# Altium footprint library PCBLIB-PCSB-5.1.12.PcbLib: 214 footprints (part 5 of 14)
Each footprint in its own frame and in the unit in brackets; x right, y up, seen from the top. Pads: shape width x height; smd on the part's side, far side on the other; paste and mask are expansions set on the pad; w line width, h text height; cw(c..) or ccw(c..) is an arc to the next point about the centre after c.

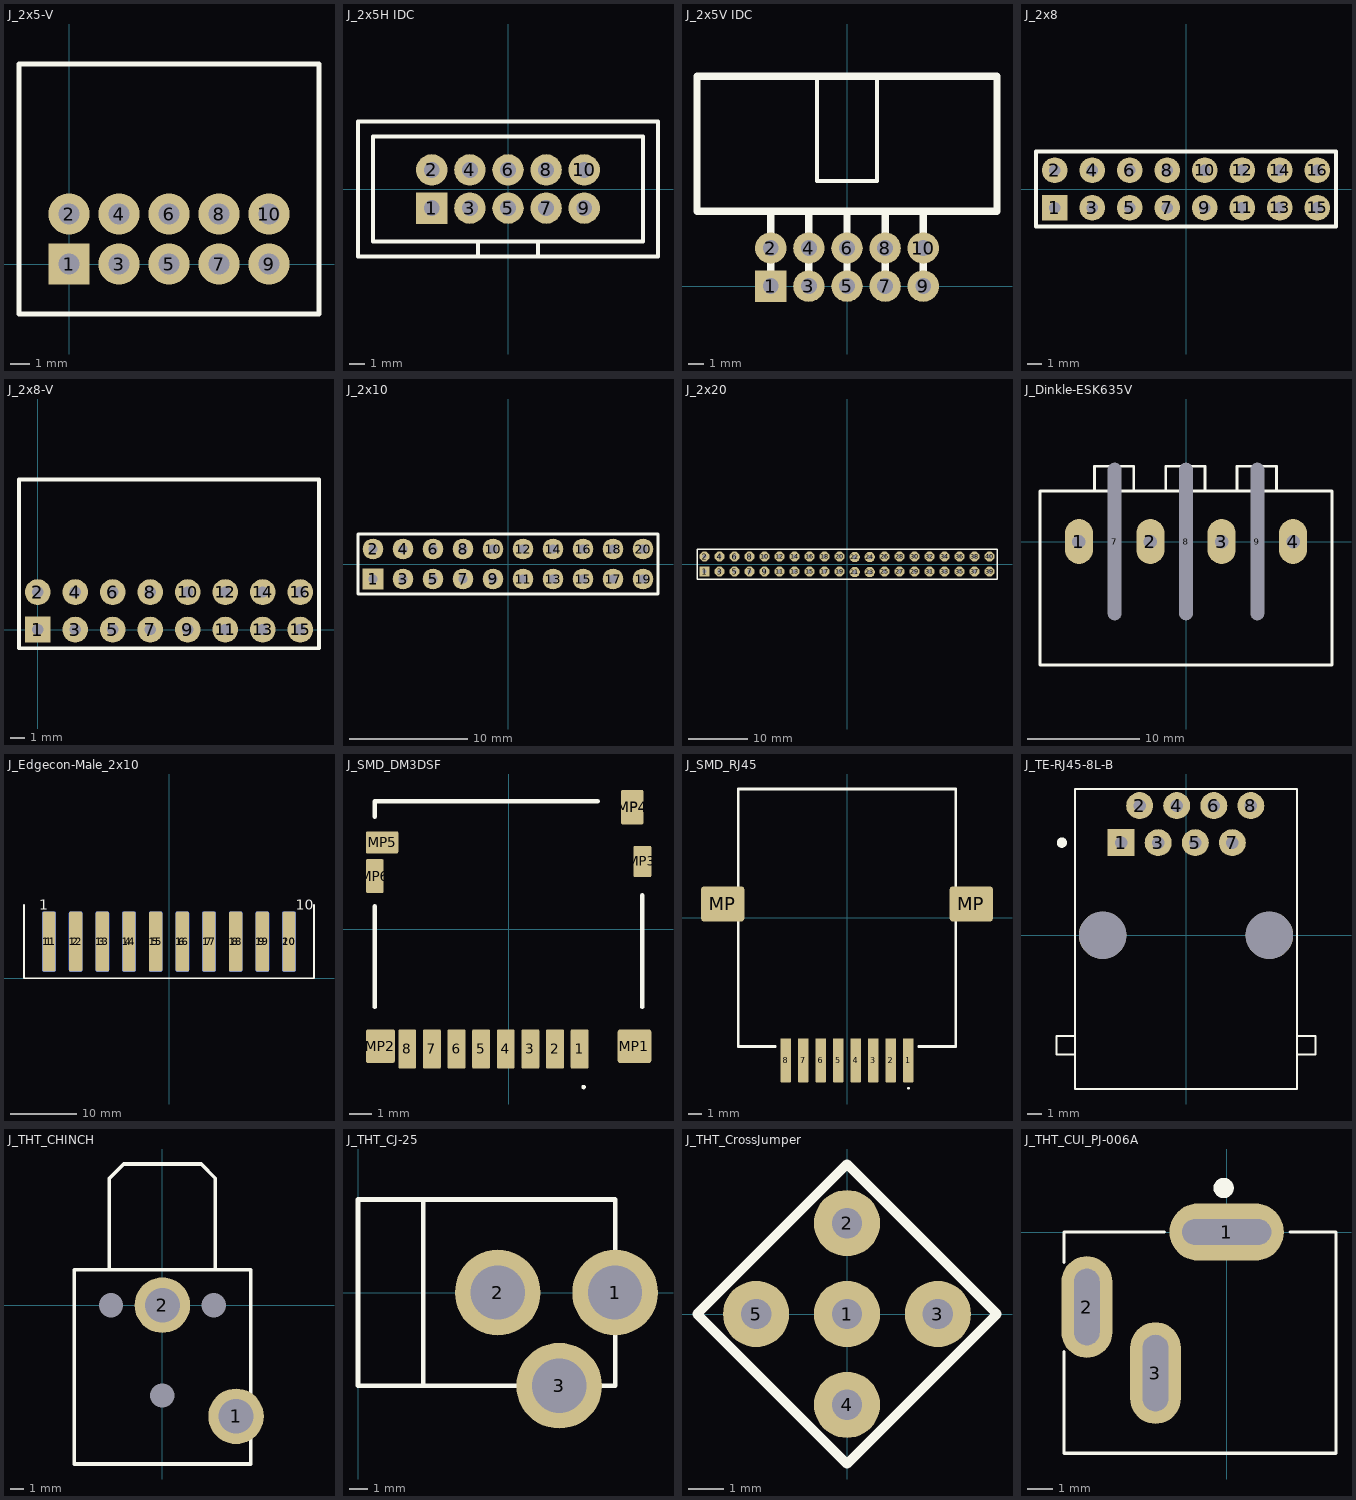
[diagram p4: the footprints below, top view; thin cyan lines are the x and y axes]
## J_2x5-V [mm] "LB-2024-04-19"
height 9
pads (10):
  rect 2.1x2.1 hole 1.05 mask+0.102: 1(0,0)
  round 2.1 hole 1.05 mask+0.102: 2(0,2.54) 3(2.54,0) 4(2.54,2.54) 5(5.08,0) 6(5.08,2.54) 7(7.62,0) 8(7.62,2.54) 9(10.16,0) 10(10.16,2.54)
Top Overlay:
  lines w0.254: -2.54,-2.54 -2.54,10.16 12.7,10.16 12.7,7.62 12.7,-2.54 -2.54,-2.54

## J_2x5H IDC [mm] "LB-2024-04-19"
height 9
pads (10):
  rect 2.1x2.1 hole 1.05 mask+0.102: 1(-5.08,-1.27)
  round 2.1 hole 1.05 mask+0.102: 2(-5.08,1.27) 3(-2.54,-1.27) 4(-2.54,1.27) 5(0,-1.27) 6(0,1.27) 7(2.54,-1.27) 8(2.54,1.27) 9(5.08,-1.27) 10(5.08,1.27)
Top Overlay:
  lines w0.254: -2,-4.5 -2,-3.5 ; -0.5,4.5 10,4.5 10,-4.5 -10,-4.5 -10,4.5 0,4.5 ; 2,-4.5 2,-3.5 ; -9,-3.5 9,-3.5 9,3.5 -9,3.5 -9,-3.5

## J_2x5V IDC [mm] "LB-2024-04-19"
height 9
pads (10):
  rect 2.1x2.1 hole 1.05 mask+0.102: 1(-5.08,0)
  round 2.1 hole 1.05 mask+0.102: 2(-5.08,2.54) 3(-2.54,0) 4(-2.54,2.54) 5(0,0) 6(0,2.54) 7(2.54,0) 8(2.54,2.54) 9(5.08,0) 10(5.08,2.54)
Top Overlay:
  lines w0.254: -2,14 -2,7 2,7 2,14
  lines w0.5: -5.08,0 -5.08,5 ; -2.54,0 -2.54,5 ; 0,0 0,5 ; 2.54,0 2.54,5 ; 5.08,0 5.08,5 ; 0,5 -10,5 -10,14 10,14 10,5 0,5

## J_2x8 [mm] "LB-2024-04-19"
pads (16):
  rect 1.75x1.75 hole 0.75: 1(-8.89,-1.27)
  round 1.75 hole 0.75: 2(-8.89,1.27) 3(-6.35,-1.27) 4(-6.35,1.27) 5(-3.81,-1.27) 6(-3.81,1.27) 7(-1.27,-1.27) 8(-1.27,1.27) 9(1.27,-1.27) 10(1.27,1.27) 11(3.81,-1.27) 12(3.81,1.27) 13(6.35,-1.27) 14(6.35,1.27) 15(8.89,-1.27) 16(8.89,1.27)
Top Overlay:
  lines w0.254: -10.16,-2.54 -10.16,2.54 10.16,2.54 10.16,-2.54 -10.16,-2.54

## J_2x8-V [mm] "LB-2024-04-19"
pads (16):
  rect 1.75x1.75 hole 0.75: 1(0,0)
  round 1.75 hole 0.75: 2(0,2.54) 3(2.54,0) 4(2.54,2.54) 5(5.08,0) 6(5.08,2.54) 7(7.62,0) 8(7.62,2.54) 9(10.16,0) 10(10.16,2.54) 11(12.7,0) 12(12.7,2.54) 13(15.24,0) 14(15.24,2.54) 15(17.78,0) 16(17.78,2.54)
Top Overlay:
  lines w0.254: -1.27,-1.27 -1.27,10.16 19.05,10.16 19.05,-1.27 -1.27,-1.27

## J_2x10 [mm] "LB-2024-4-19"
pads (20):
  rect 1.75x1.75 hole 0.75: 1(-11.43,-1.27)
  round 1.75 hole 0.75: 2(-11.43,1.27) 3(-8.89,-1.27) 4(-8.89,1.27) 5(-6.35,-1.27) 6(-6.35,1.27) 7(-3.81,-1.27) 8(-3.81,1.27) 9(-1.27,-1.27) 10(-1.27,1.27) 11(1.27,-1.27) 12(1.27,1.27) 13(3.81,-1.27) 14(3.81,1.27) 15(6.35,-1.27) 16(6.35,1.27) 17(8.89,-1.27) 18(8.89,1.27) 19(11.43,-1.27) 20(11.43,1.27)
Top Overlay:
  lines w0.254: -12.7,-2.54 12.7,-2.54 12.7,2.54 -12.7,2.54 -12.7,-2.54

## J_2x20 [mm] "LB-2024-4-19"
pads (40):
  rect 1.75x1.75 hole 0.75: 1(-24.13,-1.224)
  round 1.75 hole 0.75: 2(-24.13,1.316) 3(-21.59,-1.224) 4(-21.59,1.316) 5(-19.05,-1.224) 6(-19.05,1.316) 7(-16.51,-1.224) 8(-16.51,1.316) 9(-13.97,-1.224) 10(-13.97,1.316) 11(-11.43,-1.224) 12(-11.43,1.316) 13(-8.89,-1.224) 14(-8.89,1.316) 15(-6.35,-1.224) 16(-6.35,1.316) 17(-3.81,-1.224) 18(-3.81,1.316) 19(-1.27,-1.224) 20(-1.27,1.316) 21(1.296,-1.316) 22(1.296,1.224) 23(3.836,-1.316) 24(3.836,1.224) 25(6.35,-1.224) 26(6.35,1.316) 27(8.89,-1.224) 28(8.89,1.316) 29(11.43,-1.224) 30(11.43,1.316) 31(13.97,-1.224) 32(13.97,1.316) 33(16.51,-1.224) 34(16.51,1.316) 35(19.05,-1.224) 36(19.05,1.316) 37(21.59,-1.224) 38(21.59,1.316) 39(24.13,-1.224) 40(24.13,1.316)
Top Overlay:
  lines w0.254: -25.4,-2.494 25.4,-2.494 25.4,2.586 -25.4,2.586 -25.4,-2.494

## J_Dinkle-ESK635V [mm] "LB-2025-06-18"
pads (7):
  oval 2.5x4 hole 1.2: 1(-9.525,0) 2(-3.175,0) 3(3.175,0) 4(9.525,0)
  oval 1x14 hole 1.2 slot 14 at 90 deg: 7(-6.35,0) 8(0,0) 9(6.35,0)
Top Overlay:
  lines w0.254: -8.15,4.55 -8.15,6.7 -4.65,6.7 -4.65,4.55 ; -1.8,4.5 -1.8,6.7 1.7,6.7 1.7,4.5 ; 0,4.5 13,4.5 ; 4.55,4.55 4.55,6.7 8.05,6.7 8.05,4.55 ; 13,4.5 -13,4.5 -13,-11 13,-11 13,0 13,4.5

## J_Edgecon-Male_2x10 [mm] "PS-2024-06-15"
pads (20):
  rrect25% 2x9 smd paste-0.02 mask+0.05: 1(-18,5.5) 2(-14,5.5) 3(-10,5.5) 4(-6,5.5) 5(-2,5.5) 6(2,5.5) 7(6,5.5) 8(10,5.5) 9(14,5.5) 10(18,5.5)
  rrect25% 2x9 smd far side paste-0.02 mask+0.05: 11(-18,5.5) 12(-14,5.5) 13(-10,5.5) 14(-6,5.5) 15(-2,5.5) 16(2,5.5) 17(6,5.5) 18(10,5.5) 19(14,5.5) 20(18,5.5)
Bottom Layer:
  lines w0.254: -18,8.75 -18,9
Top Overlay:
  lines w0.254: -21.75,11 -21.75,10.75 -21.75,0 0,0 21.75,0 21.75,11
  text "1" at -19.496,10.254 h1.52
  text "10" at 19.004,10.254 h1.52
Bottom Overlay:
  text "11" at -18.754,10.254 h1.52
  text "20" at 21.496,10.254 h1.52

## J_SMD_DM3DSF [mm] "LB-2025-02-19"
pads (14):
  rrect15% 0.8x1.75 smd paste-0.02 mask+0.05: 1(3.175,-5.35) 2(2.075,-5.35) 3(0.975,-5.35) 4(-0.125,-5.35) 5(-1.225,-5.35) 6(-2.325,-5.35) 7(-3.425,-5.35) 8(-4.525,-5.35)
  rrect15% 1.5x1.5 smd paste-0.02 mask+0.05: MP1(5.625,-5.225)
  rrect15% 1.3x1.5 smd paste-0.02 mask+0.05: MP2(-5.725,-5.225)
  rrect15% 0.8x1.4 smd paste-0.02 mask+0.05: MP3(5.975,3.025)
  rrect15% 1x1.55 smd paste-0.02 mask+0.05: MP4(5.525,5.45)
  rrect15% 1.45x1 smd paste-0.02 mask+0.05: MP5(-5.65,3.875)
  rrect15% 0.8x1.5 smd paste-0.02 mask+0.05: MP6(-5.975,2.375)
Top Overlay:
  lines w0.1: 3.35,-7.1 ccw(c3.35,-7.05) 3.35,-7 ccw(c3.35,-7.05) 3.35,-7.1
  lines w0.2: -5.975,-3.475 -5.975,1.025 ; -5.975,5.025 -5.975,5.725 3.975,5.725 ; 5.975,-3.475 5.975,1.525

## J_SMD_RJ45 [mm] "LB-2024-05-31"
pads (10):
  rrect15% 0.76x3.185 smd paste-0.02 mask+0.05: 1(4.445,-10.325) 2(3.175,-10.325) 3(1.905,-10.325) 4(0.635,-10.325) 5(-0.635,-10.325) 6(-1.905,-10.325) 7(-3.175,-10.325) 8(-4.445,-10.325)
  rrect15% 3.12x2.54 smd paste-0.02 mask+0.05: MP(-9,1) MP(9,1)
Top Overlay:
  lines w0.1: 4.445,-12.4 cw(c4.445,-12.35) 4.445,-12.3 cw(c4.445,-12.35) 4.445,-12.4
  lines w0.2: -5.2,-9.325 -7.87,-9.325 -7.87,2.6 -7.87,5.8 -7.87,9.325 7.87,9.325 7.87,2.6 7.87,-9.325 5.2,-9.325

## J_TE-RJ45-8L-B [mm] "LB-2024-11-29"
pads (10):
  rect 1.85x1.85 hole 0.85: 1(-4.445,6.35)
  round 1.85 hole 0.85: 2(-3.175,8.89) 3(-1.905,6.35) 4(-0.635,8.89) 5(0.635,6.35) 6(1.905,8.89) 7(3.175,6.35) 8(4.445,8.89)
  round 3.25 hole 3.25 unplated: ""(-5.715,0) ""(5.715,0)
Top Overlay:
  circle w0.4: c-8.509,6.35 r0.15
  lines w0.127: -7.62,-8.18 -8.89,-8.18 -8.89,-6.91 -7.62,-6.91 ; -7.62,-8.18 -7.62,-6.91 ; -7.62,-8.18 -7.62,-10.54 7.62,-10.54 7.62,-8.18 ; -7.62,-6.91 -7.62,10.03 7.62,10.03 7.62,-6.91 ; 7.62,-8.18 8.89,-8.18 8.89,-6.91 7.62,-6.91 ; 7.62,-8.18 7.62,-6.91

## J_THT_CHINCH [mm] "LB-2024-04-19"
pads (5):
  round 4 hole 2.5: 1(5.3,-8) 2(0,0)
  round 0.5 hole 1.75: 3(-3.7,0) 3(0,-6.5) 3(3.7,0)
Top Overlay:
  lines w0.254: -3.81,2.54 -3.81,9.144 -2.794,10.16 2.794,10.16 3.81,9.144 3.81,2.54 ; -6.35,-11.43 6.35,-11.43 6.35,2.54 5.08,2.54 -5.08,2.54 -6.35,2.54 -6.35,-11.43

## J_THT_CJ-25 [mm] "LB-2024-04-19"
height 1.7
pads (3):
  round 4.6 hole 2.9: 1(13.8,0) 2(7.5,0) 3(10.8,-5)
Top Overlay:
  lines w0.254: 3.5,-5 3.5,5 ; 0,-5 0,5 13.8,5 13.8,-5 0,-5

## J_THT_CrossJumper [mm] "LB-2024-04-19"
pads (5):
  round 1.85 hole 0.85: 1(0,0) 2(0,2.54) 3(2.54,0) 4(0,-2.54) 5(-2.54,0)
Top Overlay:
  lines w0.254: -4.191,0 0,-4.191 4.191,0 0,4.191 -4.191,0

## J_THT_CUI_PJ-006A [mm] "LB-2024-12-12"
pads (3):
  oval 4.5x2.25 hole 1 slot 3.5 at 0 deg: 1(0,0)
  oval 2x4 hole 1 slot 3 at 90 deg: 2(-5.5,-2.95) 3(-2.8,-5.55)
Top Overlay:
  circle w0.4: c-0.12,1.73 r0.2
  lines w0.127: -6.4,-4.7 -6.4,-8.7 4.3,-8.7 4.3,0 2.5,0 ; -6.4,-1.2 -6.4,0 -2.45,0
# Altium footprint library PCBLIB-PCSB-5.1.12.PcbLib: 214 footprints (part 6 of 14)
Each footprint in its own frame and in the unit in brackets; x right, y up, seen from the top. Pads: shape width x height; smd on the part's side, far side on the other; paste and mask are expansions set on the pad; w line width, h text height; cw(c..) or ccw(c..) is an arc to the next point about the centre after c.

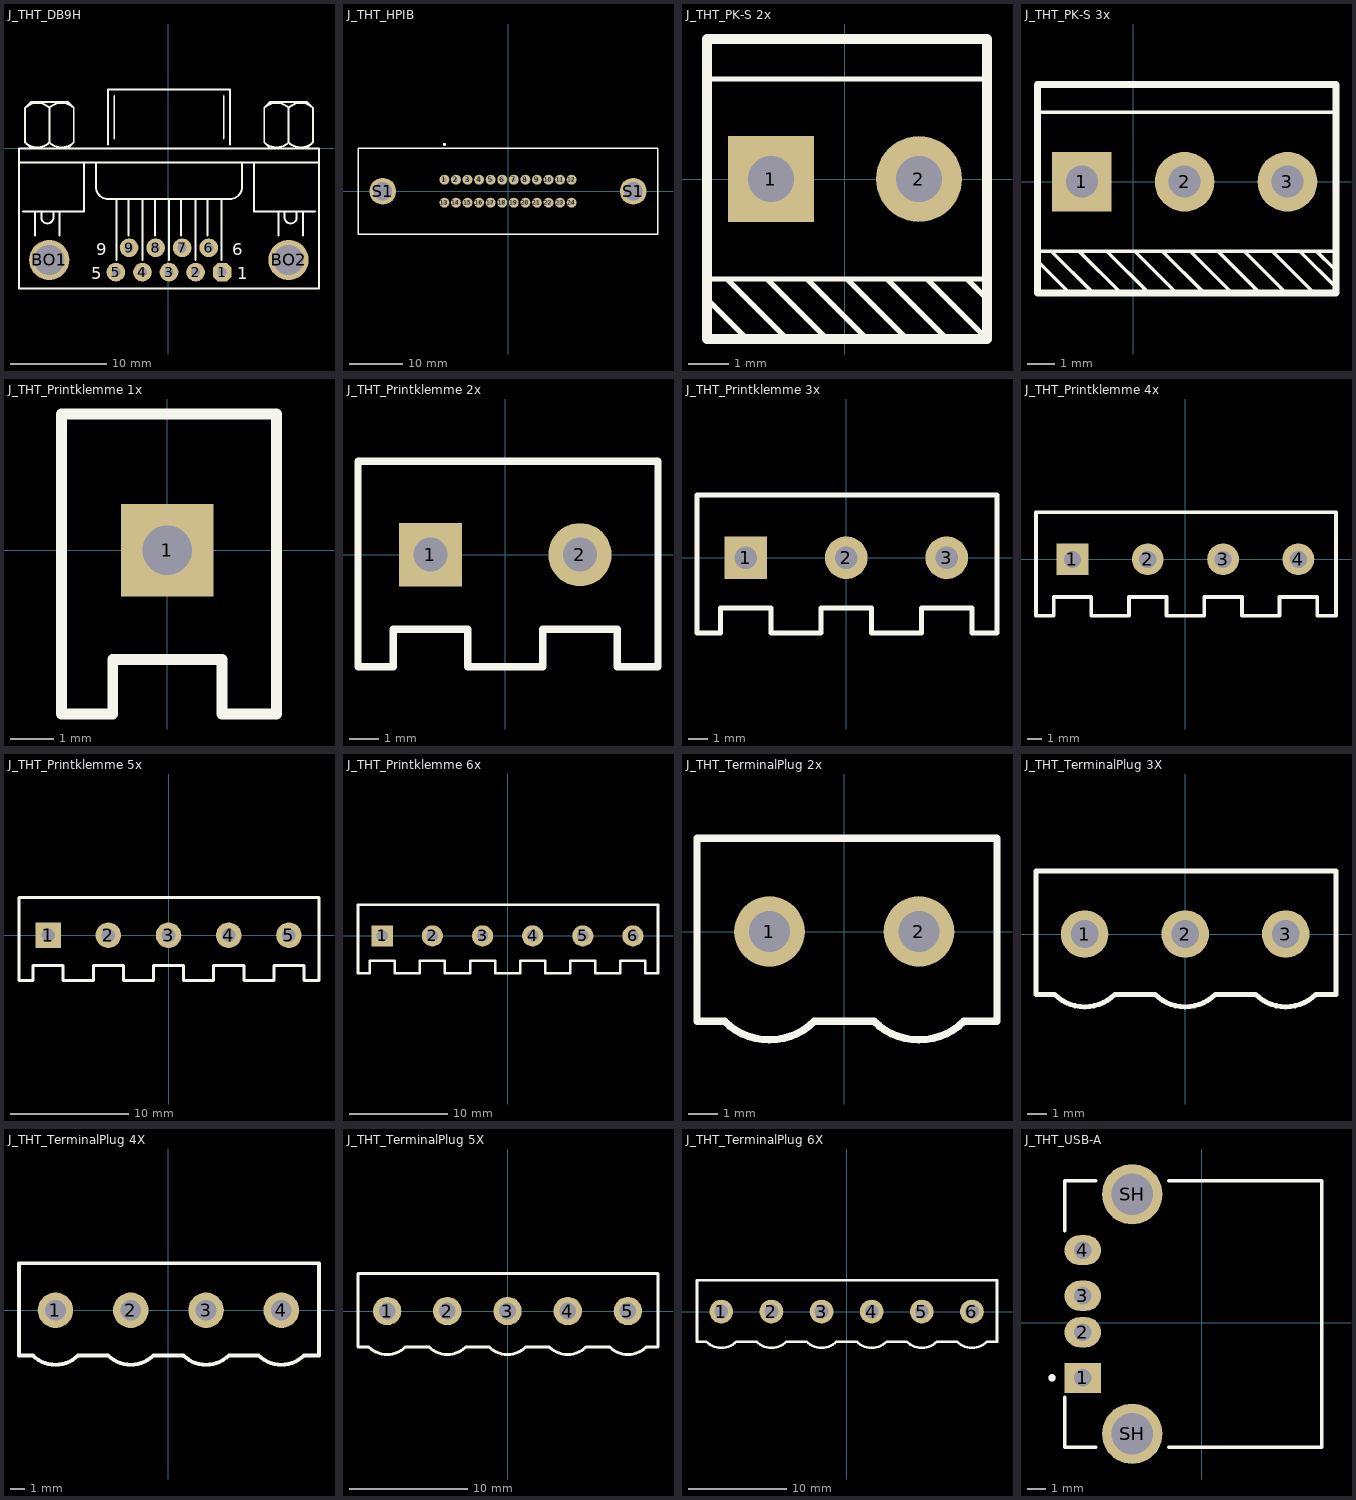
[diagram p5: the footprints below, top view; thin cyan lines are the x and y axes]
## J_THT_DB9H [mm] "LB-2024-04-17"
pads (11):
  oct 1.95x1.95 hole 0.95: 1(5.6,-12.937)
  round 1.95 hole 0.95: 2(2.827,-12.937) 3(0.054,-12.937) 4(-2.718,-12.937) 5(-5.491,-12.937) 6(4.203,-10.397) 7(1.43,-10.397) 8(-1.343,-10.397) 9(-4.115,-10.397)
  round 4.2 hole 3.15: BO1(-12.455,-11.667) BO2(12.543,-11.667)
Top Overlay:
  lines w0.203: -15.609,-1.507 15.718,-1.507 ; -15.186,-6.587 -8.836,-6.587 -8.836,-1.507 ; -14.976,0.608 ccw(c-13.704,1.88) -12.432,0.608 ; -14.976,4.211 cw(c-13.704,2.938) -12.432,4.211 ; -14.339,-0.025 -14.974,0.61 -14.974,4.208 -14.339,4.843 -10.529,4.843 -9.894,4.208 -9.894,0.61 -10.529,-0.025 ; -13.916,-9.127 -13.916,-6.587 ; -13.281,-6.587 -13.281,-7.222 ccw(c-12.646,-7.222) -12.011,-7.222 -12.011,-6.587 ; -12.436,0.608 ccw(c-11.164,1.88) -9.892,0.608 ; -12.436,4.211 cw(c-11.164,2.938) -9.892,4.211 ; -12.434,0.61 -12.434,4.208 ; -11.376,-9.127 -11.376,-6.587 ; -7.566,-1.507 -7.566,-4.047 ccw(c-6.296,-4.047) -6.296,-5.317 6.404,-5.317 ccw(c6.404,-4.047) 7.674,-4.047 7.674,-1.507 ; -6.296,0.398 -6.296,6.113 6.404,6.113 6.404,0.398 ; -5.661,1.033 -5.661,5.478 ; -5.449,-11.667 -5.449,-5.317 ; -4.179,-9.127 -4.179,-5.317 ; -2.697,-11.667 -2.697,-5.317 ; -1.427,-9.127 -1.427,-5.317 ; 0.054,-11.667 0.054,-5.317 ; 1.324,-9.127 1.324,-5.317 ; 2.806,-11.667 2.806,-5.317 ; 4.076,-9.127 4.076,-8.915 4.076,-5.317 ; 5.558,-11.667 5.558,-5.317 ; 5.769,1.033 5.769,5.478 ; 8.944,-1.507 8.944,-6.587 15.294,-6.587 ; 10,0.608 ccw(c11.273,1.88) 12.545,0.608 ; 10,4.211 cw(c11.273,2.938) 12.545,4.211 ; 10.638,-0.025 10.003,0.61 10.003,4.208 10.638,4.843 14.448,4.843 15.083,4.208 15.083,0.61 14.448,-0.025 ; 11.484,-9.127 11.484,-6.587 ; 12.119,-6.587 12.119,-7.222 ccw(c12.754,-7.222) 13.389,-7.222 13.389,-6.587 ; 12.54,0.608 ccw(c13.813,1.88) 15.085,0.608 ; 12.54,4.211 cw(c13.813,2.938) 15.085,4.211 ; 12.543,0.61 12.543,4.208 ; 14.024,-9.127 14.024,-6.587 ; -15.609,-14.63 -15.609,-0.025 15.718,-0.025 15.718,-14.63 -15.609,-14.63
  text "9" at -7.566,-11.159 h1.27
  text "5" at -8.074,-13.699 h1.27
  text "1" at 7.166,-13.699 h1.27
  text "6" at 6.658,-11.159 h1.27

## J_THT_HPIB [mm] "LB-24-10-23"
pads (26):
  round 1.85 hole 0.85: 1(-11.88,2.16) 2(-9.72,2.16) 3(-7.56,2.16) 4(-5.4,2.16) 5(-3.24,2.16) 6(-1.08,2.16) 7(1.08,2.16) 8(3.24,2.16) 9(5.4,2.16) 10(7.56,2.16) 11(9.72,2.16) 12(11.88,2.16) 13(-11.88,-2.13) 14(-9.72,-2.13) 15(-7.56,-2.13) 16(-5.4,-2.13) 17(-3.24,-2.13) 18(-1.08,-2.13) 19(1.08,-2.13) 20(3.24,-2.13) 21(5.4,-2.13) 22(7.56,-2.13) 23(9.72,-2.13) 24(11.88,-2.13)
  round 5 hole 3.5: S1(-23.39,0) S1(23.39,0)
Top Overlay:
  circle w0.4: c-11.88,8.75 r0.1
  lines w0.254: -28.005,-8.005 -28.005,8.005 28.005,8.005 28.005,-8.005 -28.005,-8.005

## J_THT_PK-S 2x [mm] "LB-2024-05-03g"
pads (2):
  rect 2.15x2.15 hole 1.15: 1(-1.85,0)
  round 2.15 hole 1.15: 2(1.85,0)
Top Overlay:
  lines w0.127: -3.45,2.5 3.55,2.5 ; -2.45,-4 -3.45,-3 -3.45,-2.5 3.55,-2.5 ; -1.95,-2.5 -0.45,-4 ; -1.45,-4 -2.95,-2.5 ; -0.95,-2.5 0.55,-4 ; 0.05,-2.5 1.55,-4 ; 1.05,-2.5 2.55,-4 ; 3.55,-4 2.05,-2.5 ; 3.55,-3 3.05,-2.5 ; -2.95,-2.5 -2.95,-2.5 ; 2.05,-2.5 2.05,-2.5 ; 3.05,-2.5 3.05,-2.5 ; 3.05,-2.5 3.05,-2.5
  lines w0.254: -3.45,-4 -3.45,2.365 -3.45,3.5 3.55,3.5 3.55,-4 -2.91,-4 -3.45,-4

## J_THT_PK-S 3x [mm] "LB-2024-05-03g"
pads (3):
  rect 2.15x2.15 hole 1.15: 1(-1.85,0)
  round 2.15 hole 1.15: 2(1.85,0) 3(5.55,0)
Top Overlay:
  lines w0.127: -3.5,-2.5 6.5,-2.5 7.3,-2.5 ; -3.45,2.5 7.3,2.5 ; -3.4,-2.9 -2.3,-4 ; -1.95,-2.5 -0.45,-4 ; -1.45,-4 -2.95,-2.5 ; -0.95,-2.5 0.55,-4 ; 0.05,-2.5 1.55,-4 ; 1.05,-2.5 2.55,-4 ; 3.55,-4 2.05,-2.5 ; 4,-2.5 5.425,-3.925 ; 4.575,-4.025 3.05,-2.5 ; 5,-2.5 6.5,-4 ; 6,-2.5 7.3,-3.8 ; 7,-2.5 6.6,-2.5 7.25,-3.15 ; -2.95,-2.5 -2.95,-2.5 ; 2.05,-2.5 2.05,-2.5 ; 3.05,-2.5 3.05,-2.5 ; 3.05,-2.5 3.05,-2.5
  lines w0.254: -3.45,-4 -3.45,2.365 -3.45,3.5 7.3,3.5 7.3,-4 3.55,-4 -2.91,-4 -3.45,-4

## J_THT_Printklemme 1x [mm] "LB-2024-04-17"
pads (1):
  rect 2.15x2.15 hole 1.15: 1(0,0)
Top Overlay:
  lines w0.254: -2.46,-3.81 -2.46,2.365 -2.46,3.175 2.54,3.175 2.54,-3.81 1.27,-3.81 1.27,-2.54 -1.27,-2.54 -1.27,-3.81 -2.46,-3.81

## J_THT_Printklemme 2x [mm] "LB-2024-04-17"
pads (2):
  rect 2.15x2.15 hole 1.15: 1(-2.54,0)
  round 2.15 hole 1.15: 2(2.54,0)
Top Overlay:
  lines w0.254: 1.27,-3.81 1.27,-2.54 ; 1.27,-3.81 -1.27,-3.81 -1.27,-2.54 -3.81,-2.54 -3.81,-3.81 -5,-3.81 -5,2.365 -5,3.175 5.19,3.175 5.19,-3.81 3.81,-3.81 ; 1.27,-3.81 1.27,-2.54 ; 1.27,-2.54 3.81,-2.54 ; 3.81,-3.81 3.81,-2.54 ; 3.81,-3.81 3.81,-2.54

## J_THT_Printklemme 3x [mm] "LB-2024-04-17"
pads (3):
  rect 2.15x2.15 hole 1.15: 1(-5.08,0)
  round 2.15 hole 1.15: 2(0,0) 3(5.08,0)
Top Overlay:
  lines w0.254: -1.27,-3.81 -1.27,-2.54 ; -1.27,-3.81 -3.81,-3.81 -3.81,-2.54 -6.35,-2.54 -6.35,-3.81 -7.54,-3.81 -7.54,2.365 -7.54,3.175 2.65,3.175 7.62,3.175 7.62,-3.81 6.35,-3.81 6.35,-2.54 3.81,-2.54 3.81,-3.81 1.27,-3.81 ; -1.27,-3.81 -1.27,-2.54 ; -1.27,-2.54 1.27,-2.54 ; 1.27,-3.81 1.27,-2.54 ; 1.27,-3.81 1.27,-2.54

## J_THT_Printklemme 4x [mm] "LB-2024-04-17"
pads (4):
  rect 2.15x2.15 hole 1.15: 1(-7.62,0)
  round 2.15 hole 1.15: 2(-2.54,0) 3(2.54,0) 4(7.62,0)
Top Overlay:
  lines w0.254: -3.81,-3.81 -3.81,-2.54 ; -3.81,-3.81 -6.35,-3.81 -6.35,-2.54 -8.89,-2.54 -8.89,-3.81 -10.08,-3.81 -10.08,2.365 -10.08,3.175 0.11,3.175 10.16,3.175 10.16,-3.81 8.89,-3.81 8.89,-2.54 6.35,-2.54 6.35,-3.81 3.81,-3.81 3.81,-2.54 1.27,-2.54 1.27,-3.81 -1.27,-3.81 ; -3.81,-3.81 -3.81,-2.54 ; -3.81,-2.54 -1.27,-2.54 ; -1.27,-3.81 -1.27,-2.54 ; -1.27,-3.81 -1.27,-2.54

## J_THT_Printklemme 5x [mm] "LB-2024-04-17"
pads (5):
  rect 2.15x2.15 hole 1.15: 1(-10.16,0)
  round 2.15 hole 1.15: 2(-5.08,0) 3(0,0) 4(5.08,0) 5(10.16,0)
Top Overlay:
  lines w0.254: -6.35,-3.81 -6.35,-2.54 ; -6.35,-3.81 -8.89,-3.81 -8.89,-2.54 -11.43,-2.54 -11.43,-3.81 -12.62,-3.81 -12.62,2.365 -12.62,3.175 -2.43,3.175 12.7,3.175 12.7,-3.81 11.43,-3.81 11.43,-2.54 8.89,-2.54 8.89,-3.81 6.35,-3.81 6.35,-2.54 3.81,-2.54 3.81,-3.81 1.27,-3.81 1.27,-2.54 -1.27,-2.54 -1.27,-3.81 -3.81,-3.81 ; -6.35,-3.81 -6.35,-2.54 ; -6.35,-2.54 -3.81,-2.54 ; -3.81,-3.81 -3.81,-2.54 ; -3.81,-3.81 -3.81,-2.54

## J_THT_Printklemme 6x [mm] "LB-2024-04-17"
pads (6):
  rect 2.15x2.15 hole 1.15: 1(-12.7,0)
  round 2.15 hole 1.15: 2(-7.62,0) 3(-2.54,0) 4(2.54,0) 5(7.62,0) 6(12.7,0)
Top Overlay:
  lines w0.254: -8.89,-3.81 -8.89,-2.54 ; -8.89,-3.81 -11.43,-3.81 -11.43,-2.54 -13.97,-2.54 -13.97,-3.81 -15.16,-3.81 -15.16,2.365 -15.16,3.175 -4.97,3.175 15.24,3.175 15.24,-3.81 13.97,-3.81 13.97,-2.54 11.43,-2.54 11.43,-3.81 8.89,-3.81 8.89,-2.54 6.35,-2.54 6.35,-3.81 3.81,-3.81 3.81,-2.54 1.27,-2.54 1.27,-3.81 -1.27,-3.81 -1.27,-2.54 -3.81,-2.54 -3.81,-3.81 -6.35,-3.81 ; -8.89,-3.81 -8.89,-2.54 ; -8.89,-2.54 -6.35,-2.54 ; -6.35,-3.81 -6.35,-2.54 ; -6.35,-3.81 -6.35,-2.54

## J_THT_TerminalPlug 2x [mm] "LB-2024-04-17"
pads (2):
  round 2.4 hole 1.4: 1(-2.54,0) 2(2.54,0)
Top Overlay:
  lines w0.254: -5,-3.048 -4.064,-3.048 ccw(c-2.54,-1.524) -1.016,-3.048 1.016,-3.048 ccw(c2.54,-1.524) 4.064,-3.048 5.19,-3.048 5.19,3.175 -5,3.175 -5,2.365 -5,-3.048

## J_THT_TerminalPlug 3X [mm] "LB-2024-04-17"
pads (3):
  round 2.4 hole 1.4: 1(-5.08,0) 2(0,0) 3(5.08,0)
Top Overlay:
  lines w0.254: -7.54,-3.048 -7.54,2.365 -7.54,3.175 2.65,3.175 7.62,3.175 7.62,-3.048 6.604,-3.048 cw(c5.08,-1.524) 3.556,-3.048 1.524,-3.048 cw(c0,-1.524) -1.524,-3.048 -3.556,-3.048 cw(c-5.08,-1.524) -6.604,-3.048 -7.54,-3.048

## J_THT_TerminalPlug 4X [mm] "LB-2024-04-17"
pads (4):
  round 2.4 hole 1.4: 1(-7.62,0) 2(-2.54,0) 3(2.54,0) 4(7.62,0)
Top Overlay:
  lines w0.254: -10.08,-3.048 -10.08,2.365 -10.08,3.175 0.11,3.175 10.16,3.175 10.16,-3.048 9.144,-3.048 cw(c7.62,-1.524) 6.096,-3.048 4.064,-3.048 cw(c2.54,-1.524) 1.016,-3.048 -1.016,-3.048 cw(c-2.54,-1.524) -4.064,-3.048 -6.096,-3.048 cw(c-7.62,-1.524) -9.144,-3.048 -10.08,-3.048

## J_THT_TerminalPlug 5X [mm] "LB-2024-04-17"
pads (5):
  round 2.4 hole 1.4: 1(-10.16,0) 2(-5.08,0) 3(0,0) 4(5.08,0) 5(10.16,0)
Top Overlay:
  lines w0.254: -12.62,-3.048 -11.684,-3.048 ccw(c-10.16,-1.524) -8.636,-3.048 -6.604,-3.048 ccw(c-5.08,-1.524) -3.556,-3.048 -1.524,-3.048 ccw(c0,-1.524) 1.524,-3.048 3.556,-3.048 ccw(c5.08,-1.524) 6.604,-3.048 8.636,-3.048 ccw(c10.16,-1.524) 11.684,-3.048 12.7,-3.048 12.7,3.175 -2.43,3.175 -12.62,3.175 -12.62,2.365 -12.62,-3.048

## J_THT_TerminalPlug 6X [mm] "LB-2024-04-17"
pads (6):
  round 2.4 hole 1.4: 1(-12.7,0) 2(-7.62,0) 3(-2.54,0) 4(2.54,0) 5(7.62,0) 6(12.7,0)
Top Overlay:
  lines w0.254: -15.16,-3.048 -15.16,2.365 -15.16,3.175 -4.97,3.175 15.24,3.175 15.24,-3.048 14.224,-3.048 cw(c12.7,-1.524) 11.176,-3.048 9.144,-3.048 cw(c7.62,-1.524) 6.096,-3.048 4.064,-3.048 cw(c2.54,-1.524) 1.016,-3.048 -1.016,-3.048 cw(c-2.54,-1.524) -4.064,-3.048 -6.096,-3.048 cw(c-7.62,-1.524) -9.144,-3.048 -11.176,-3.048 cw(c-12.7,-1.524) -14.224,-3.048 -15.16,-3.048

## J_THT_USB-A [mm] "LB-2024-04-29"
pads (6):
  rect 2x1.65 hole 0.95: 1(-6.536,-3.032)
  oval 2x1.65 hole 0.95: 2(-6.536,-0.532) 3(-6.536,1.468) 4(-6.536,3.968)
  round 3.316 hole 2.3: SH(-3.826,-6.102) SH(-3.826,7.038)
Top Overlay:
  circle w0.2: c-8.226,-3.032 r0.1
  lines w0.2: -7.526,-4.097 -7.526,-6.832 -5.836,-6.832 ; -7.526,5.033 -7.526,7.768 -5.836,7.768 ; -1.816,-6.832 6.574,-6.832 6.574,7.768 -1.816,7.768
Mechanical 13:
  circle w0.2: c-8.226,-3.032 r0.1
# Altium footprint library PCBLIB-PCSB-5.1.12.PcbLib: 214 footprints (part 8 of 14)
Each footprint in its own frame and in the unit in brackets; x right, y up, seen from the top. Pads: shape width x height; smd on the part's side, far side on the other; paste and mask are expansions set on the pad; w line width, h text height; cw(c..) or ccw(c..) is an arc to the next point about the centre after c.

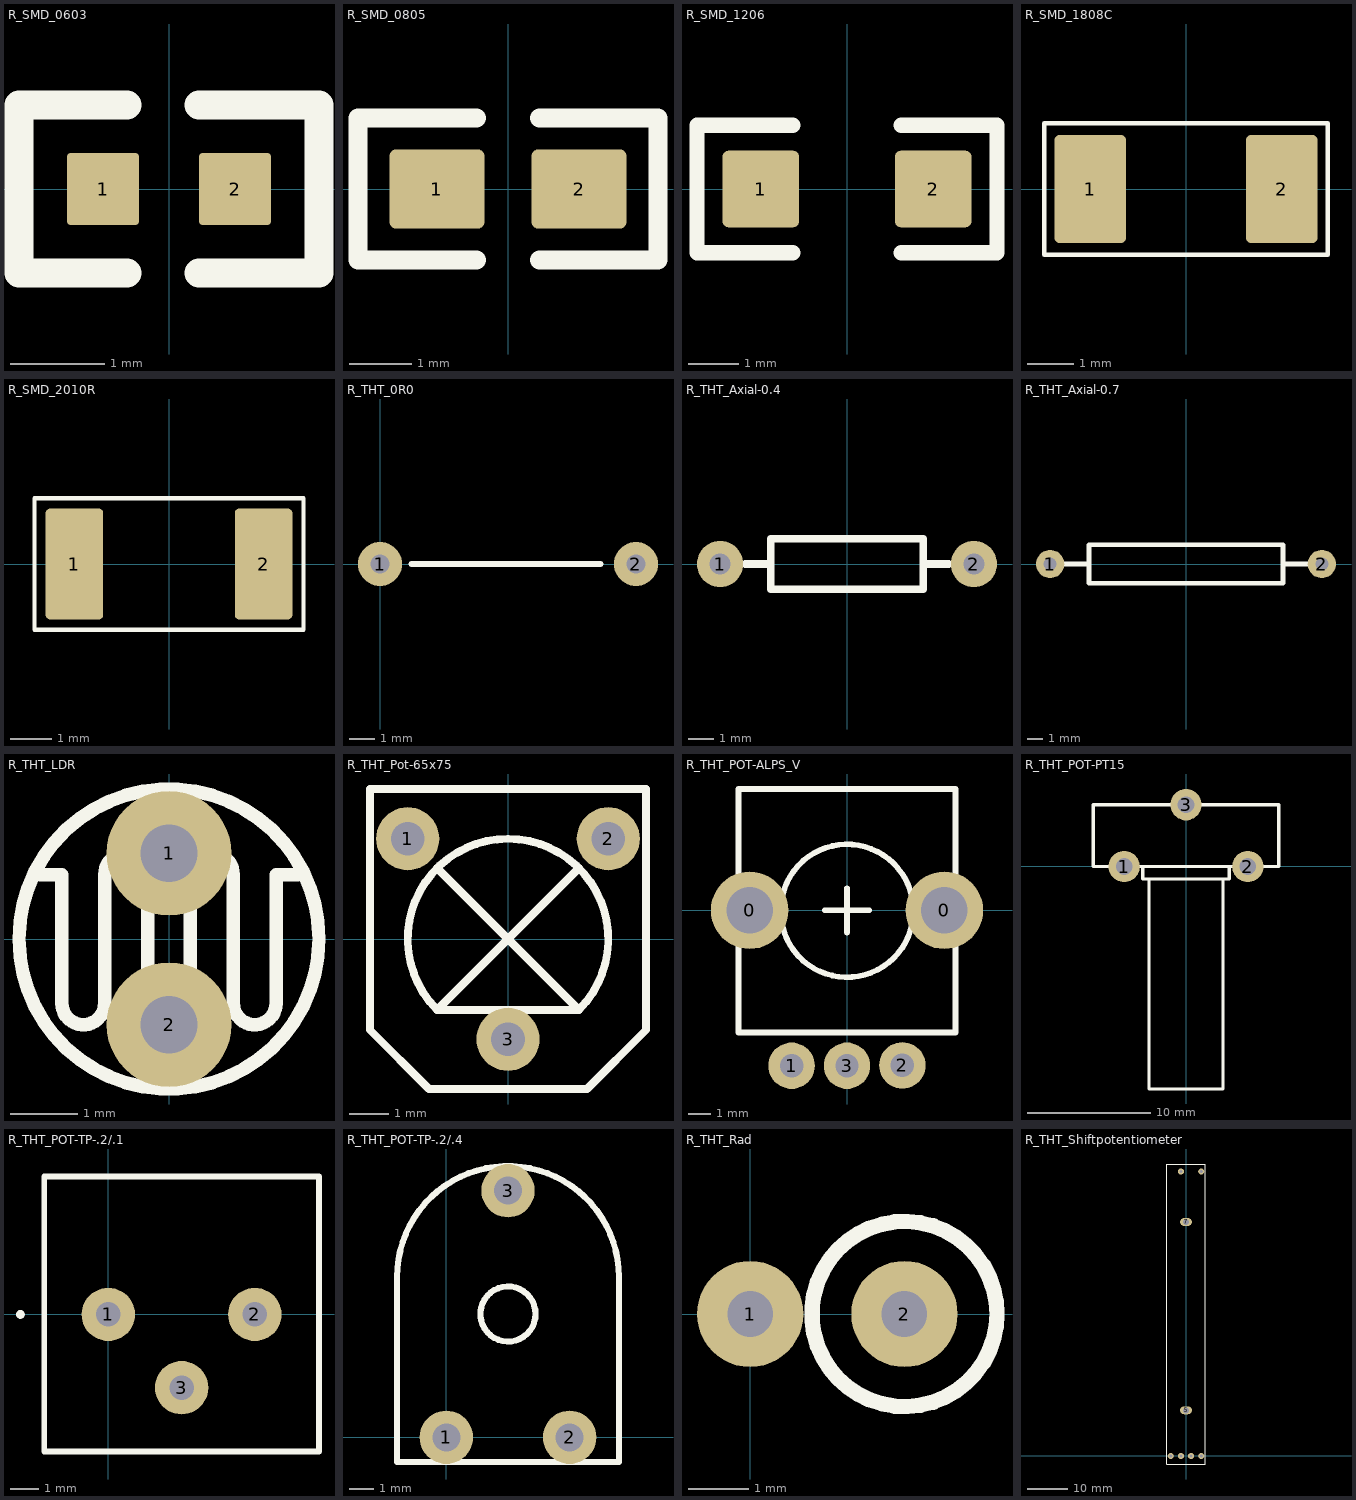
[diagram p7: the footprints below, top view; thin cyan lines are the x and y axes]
## R_SMD_0603 [mil] "LB-2024-04-17"
pads (2):
  rrect10% 30x30 smd paste-0.79 mask+1.97: 1(-27.5,0) 2(27.5,0)
Top Overlay:
  lines w12: -17.5,-35 -62.5,-35 -62.5,35 -17.5,35 ; 12.5,-35 62.5,-35 62.5,35 12.5,35

## R_SMD_0805 [mil] "LB-2024-04-17"
pads (2):
  rrect15% 60x50 smd paste-0.79 mask+1.97: 1(-45,0) 2(45,0)
Top Overlay:
  lines w12: -20,-45 -95,-45 -95,45 -20,45 ; 20,-45 95,-45 95,45 20,45

## R_SMD_1206 [mil] "LB-2024-04-17"
pads (2):
  rrect15% 60x60 smd paste-0.79 mask+1.97: 1(-67.5,0) 2(67.5,0)
Top Overlay:
  lines w12: -42.5,-50 -117.5,-50 -117.5,50 -42.5,50 ; 42.5,-50 117.5,-50 117.5,50 42.5,50

## R_SMD_1808C [mm] "LB-2024-04-17"
height 2
pads (2):
  rrect15% 1.55x2.35 smd paste-0.02 mask+0.05: 1(-2.075,0) 2(2.075,0)
Top Overlay:
  lines w0.1: -3.075,-1.425 -3.075,1.425 3.075,1.425 3.075,-1.425 -3.075,-1.425

## R_SMD_2010R [mm] "LB-2024-04-17"
height 0.7
pads (2):
  rrect15% 1.4x2.7 smd paste-0.02 mask+0.05: 1(-2.3,0) 2(2.3,0)
Top Overlay:
  lines w0.1: -3.275,-1.6 3.275,-1.6 3.275,1.6 -3.275,1.6 -3.275,-1.6

## R_THT_0R0 [mm] "LB-2024-08-13"
pads (2):
  round 1.75 hole 0.75: 1(0,0) 2(10.16,0)
Top Overlay:
  lines w0.254: 1.25,0 8.75,0

## R_THT_Axial-0.4 [mm] "LB-2024-04-17"
pads (2):
  round 1.85 hole 0.85: 1(-5.08,0) 2(5.08,0)
Top Overlay:
  lines w0.305: -4.064,0 -3.048,0 ; 3.048,0 4.064,0 ; -3.048,-1.016 3.048,-1.016 3.048,1.016 -3.048,1.016 -3.048,-1.016

## R_THT_Axial-0.7 [mm] "LB-2024-04-17"
pads (2):
  round 1.85 hole 0.85: 1(-8.89,0) 2(8.89,0)
Top Overlay:
  lines w0.305: -8.89,0 -6.35,0 ; 6.35,0 8.89,0 ; -6.35,-1.27 -6.35,1.27 6.35,1.27 6.35,-1.27 -6.35,-1.27

## R_THT_LDR [mm] "LB-2024-04-18"
pads (2):
  round 1.85 hole 0.85: 1(0,1.27) 2(0,-1.27)
Top Overlay:
  circle w0.2: c0,0 r2.222
  lines w0.2: -1.905,0.953 -1.587,0.953 -1.587,-0.953 ccw(c-1.27,-0.953) -0.953,-0.953 -0.953,0.953 cw(c-0.635,0.953) -0.318,0.953 -0.318,-0.953 ; 0.318,-0.953 0.318,0.953 cw(c0.635,0.953) 0.953,0.953 0.953,-0.953 ccw(c1.27,-0.953) 1.587,-0.953 1.587,0.953 1.905,0.953
Mechanical 13:
  lines w0.2: -0.318,-0.953 ccw(c0,-0.953) 0.318,-0.953

## R_THT_Pot-65x75 [mm]
pads (3):
  round 1.6 hole 0.85: 1(-2.54,2.54) 2(2.54,2.54) 3(0,-2.54)
Top Overlay:
  lines w0.2: -1.796,-1.796 cw(c0,0) 1.796,-1.796 ; 1.792,-1.8 -1.8,-1.8 1.8,1.8 0,0 -1.8,1.8 1.8,-1.8 ; 3.5,-2.2 3.5,-2.3 ; 3.5,-2.3 3.5,0 3.5,3.8 -3.5,3.8 -3.5,-2.3 -2,-3.8 2,-3.8 3.5,-2.3

## R_THT_POT-ALPS_V [mm]
height 15
pads (5):
  round 3.5 hole 2.1: 0(-4.4,0) 0(4.4,0)
  round 2.1 hole 1.05: 1(-2.5,-7.02) 2(2.5,-7) 3(0,-7.02)
Top Overlay:
  circle w0.254: c0,-0.02 r3
  lines w0.254: -1,0 1,0 ; 0,-1 0,0 0,1 ; -4.9,-5.52 -4.9,5.48 4.9,5.48 4.9,-5.52 -4.9,-5.52

## R_THT_POT-PT15 [mm] "LB-2024-04-17"
pads (3):
  round 2.54 hole 1.35: 1(-5.006,-0.011) 2(4.994,-0.011) 3(-0.006,4.989)
Top Overlay:
  lines w0.254: -3.506,-0.011 -3.506,-1.011 3.494,-1.011 3.494,-0.011 ; -3,-1.011 -3,-18 3,-18 3,-1.011 ; -7.506,-0.011 -7.506,4.989 7.494,4.989 7.494,-0.011 -7.506,-0.011

## R_THT_POT-TP-.2/.1 [mm] "LB-2024-12-11"
pads (3):
  round 1.85 hole 0.85: 1(0,0) 2(5.08,0) 3(2.54,-2.54)
Top Overlay:
  lines w0.2: -3.1,0 cw(c-3.05,0) -3,0 ; -3.1,0 ccw(c-3.05,0) -3,0 ; -3.1,0 cw(c-3.05,0) -3,0 ; -2.225,-4.75 -2.225,4.78 7.305,4.78 7.305,-4.75 -2.225,-4.75

## R_THT_POT-TP-.2/.4 [mm] "LB-2024-04-17"
pads (3):
  round 2.2 hole 1.15: 1(0,0) 2(5.08,0) 3(2.54,10.16)
Top Overlay:
  circle w0.254: c2.54,5.08 r1.136
  lines w0.254: -2.032,-1.016 7.112,-1.016 7.112,6.604 ccw(c2.54,6.604) -2.032,6.604 -2.032,-1.016

## R_THT_Rad [mm] "LB-2024-04-17"
pads (2):
  round 1.75 hole 0.75: 1(0,0) 2(2.54,0)
Top Overlay:
  circle w0.254: c2.54,0 r1.524

## R_THT_Shiftpotentiometer [mil] "LB-2025-01-23"
pads (8):
  round 60 hole 30: 1(-150,0) 2(-50,0) 3(50,0) 4(150,0) 5(150,2800) 6(-50,2800)
  oval 118.11x78.74 hole 59.06: 5(0,450) 7(0,2303.15)
Top Overlay:
  lines w10: -187.01,-78.74 0,-78.74 187.01,-78.74 187.01,2874.02 -187.01,2874.02 -187.01,-78.74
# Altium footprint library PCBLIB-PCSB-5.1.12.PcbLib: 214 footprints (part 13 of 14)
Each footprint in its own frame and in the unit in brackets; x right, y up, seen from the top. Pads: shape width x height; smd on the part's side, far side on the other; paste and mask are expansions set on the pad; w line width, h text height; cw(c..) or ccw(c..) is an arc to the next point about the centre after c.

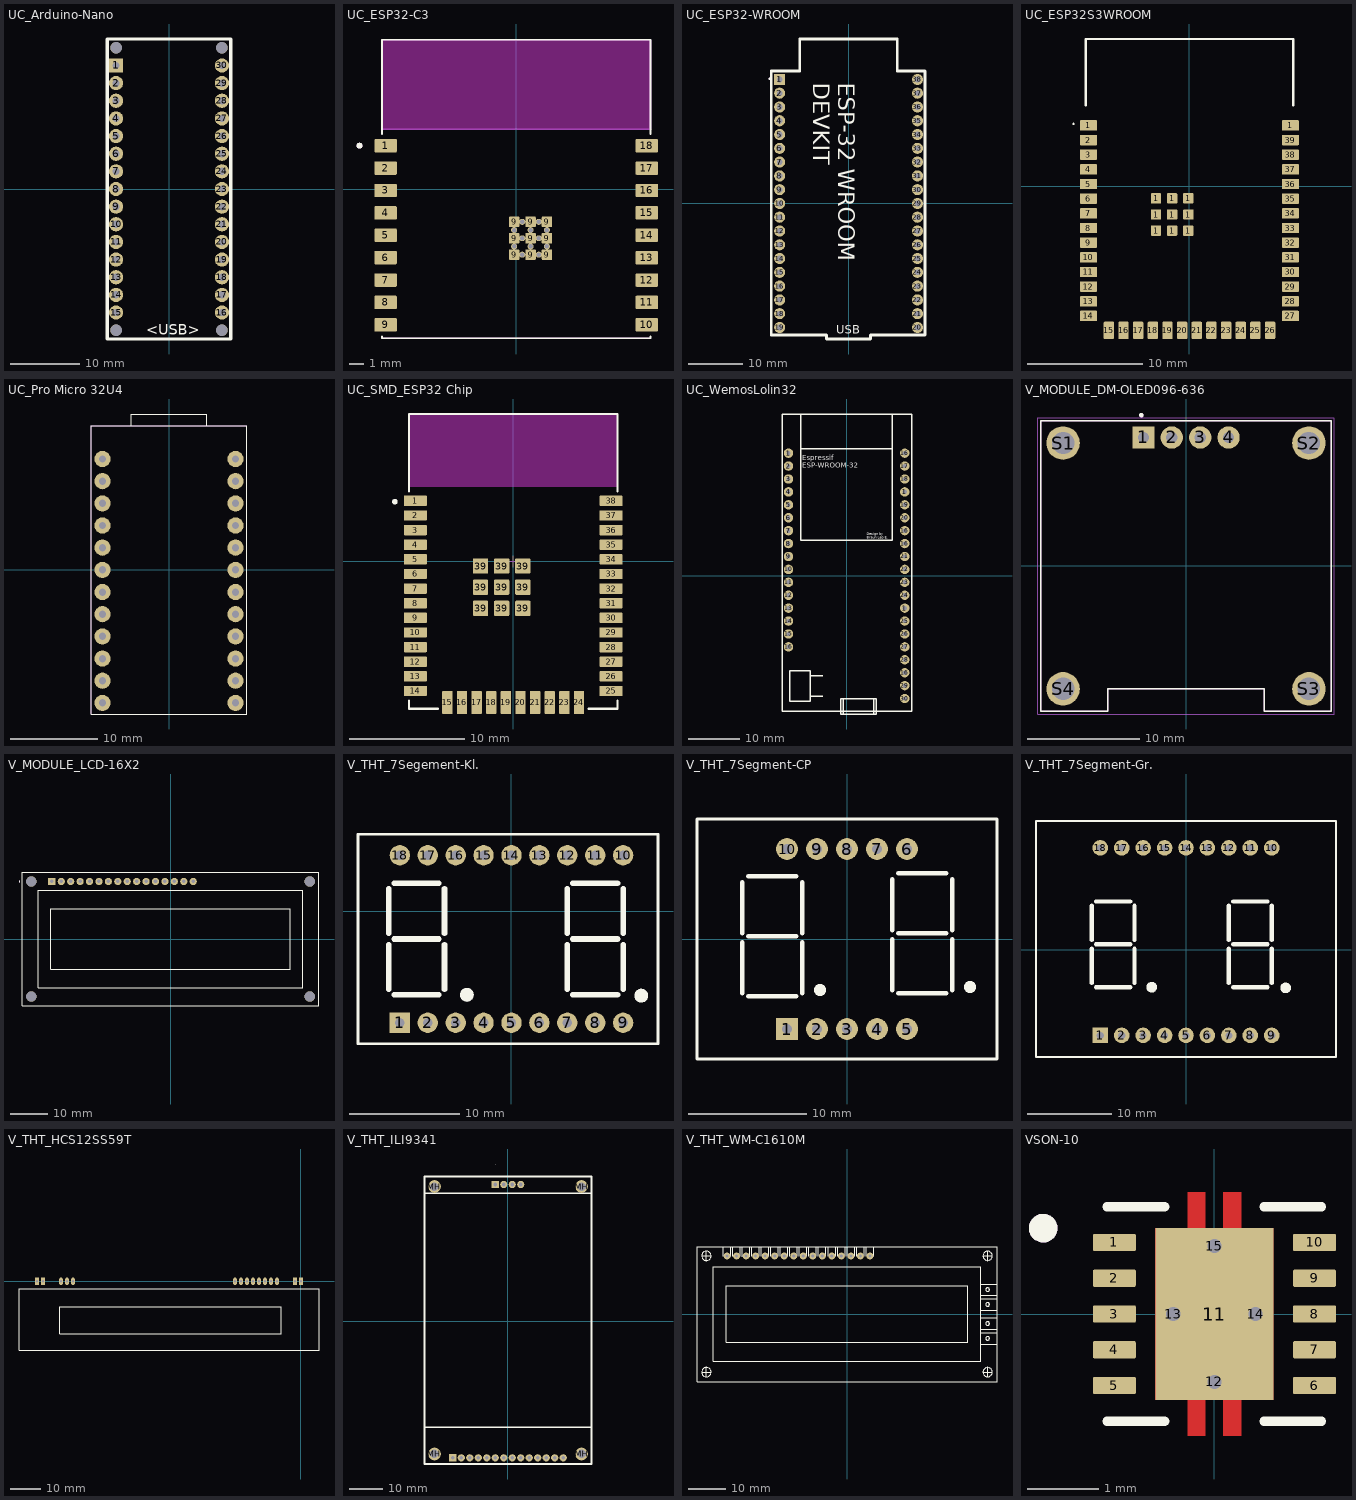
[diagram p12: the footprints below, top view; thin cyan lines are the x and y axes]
## UC_Arduino-Nano [mm] "LB-2024-04-18"
pads (34):
  rect 2.05x2.05 hole 1.05: 1(-7.62,17.78)
  round 2.05 hole 1.05: 2(-7.62,15.24) 3(-7.62,12.7) 4(-7.62,10.16) 5(-7.62,7.62) 6(-7.62,5.08) 7(-7.62,2.54) 8(-7.62,0) 9(-7.62,-2.54) 10(-7.62,-5.08) 11(-7.62,-7.62) 12(-7.62,-10.16) 13(-7.62,-12.7) 14(-7.62,-15.24) 15(-7.62,-17.78) 16(7.62,-17.78) 17(7.62,-15.24) 18(7.62,-12.7) 19(7.62,-10.16) 20(7.62,-7.62) 21(7.62,-5.08) 22(7.62,-2.54) 23(7.62,0) 24(7.62,2.54) 25(7.62,5.08) 26(7.62,7.62) 27(7.62,10.16) 28(7.62,12.7) 29(7.62,15.24) 30(7.62,17.78)
  round 1.651 hole 1.651 unplated: ""(-7.62,-20.32) ""(-7.62,20.32) ""(7.62,-20.32) ""(7.62,20.32)
Top Overlay:
  lines w0.5: -8.89,-21.59 8.89,-21.59 8.89,21.59 -8.89,21.59 -8.89,-21.59
  text "<USB>" at -3.302,-20.955 h1.52

## UC_ESP32-C3 [mm] "LB-2024-09-01"
pads (39):
  rrect15% 1.5x0.9 smd paste-0.02 mask+0.05: 1(-8.75,2.9) 2(-8.75,1.4) 3(-8.75,-0.1) 4(-8.75,-1.6) 5(-8.75,-3.1) 6(-8.75,-4.6) 7(-8.75,-6.1) 8(-8.75,-7.6) 9(-8.75,-9.1) 10(8.75,-9.1) 11(8.75,-7.6) 12(8.75,-6.1) 13(8.75,-4.6) 14(8.75,-3.1) 15(8.75,-1.6) 16(8.75,-0.1) 17(8.75,1.4) 18(8.75,2.9)
  rrect15% 0.7x0.7 smd paste-0.02 mask+0.05: 9(-0.14,-4.4) 9(-0.14,-3.3) 9(-0.14,-2.2) 9(0.96,-4.4) 9(0.96,-3.3) 9(0.96,-2.2) 9(2.06,-4.4) 9(2.06,-3.3) 9(2.06,-2.2)
  round 0.4 hole 0.3 mask+0: 9(-0.14,-3.85) 9(-0.14,-2.75) 9(0.41,-4.4) 9(0.41,-3.3) 9(0.41,-2.2) 9(0.96,-3.85) 9(0.96,-2.75) 9(1.51,-4.4) 9(1.51,-3.3) 9(1.51,-2.2) 9(2.06,-3.85) 9(2.06,-2.75)
Top Overlay:
  circle w0.2: c-10.5,2.9 r0.1
  lines w0.127: -9,-9.87 -9,-10 9,-10 9,-9.87 ; -9,3.67 -9,10 9,10 9,3.67
Keep-Out Layer:
  region: 9,4 -9,4 -9,10 9,10
  region: 9,4 -9,4 -9,10 9,10
Mechanical 13:
  circle w0.2: c-10.5,2.9 r0.1
  lines w0.127: -9,-10 9,-10 ; -9,4 9,4 9,10 -9,10 -9,4

## UC_ESP32-WROOM [mm] "LB-2024-04-18"
pads (38):
  rect 2.05x2.05 hole 1.05: 1(-12.7,22.85)
  round 2.05 hole 1.05: 2(-12.7,20.31) 3(-12.7,17.77) 4(-12.7,15.23) 5(-12.7,12.69) 6(-12.7,10.15) 7(-12.7,7.61) 8(-12.7,5.07) 9(-12.7,2.53) 10(-12.7,-0.01) 11(-12.7,-2.55) 12(-12.7,-5.09) 13(-12.7,-7.63) 14(-12.7,-10.17) 15(-12.7,-12.71) 16(-12.7,-15.25) 17(-12.7,-17.79) 18(-12.7,-20.33) 19(-12.7,-22.87) 20(12.7,-22.87) 21(12.7,-20.33) 22(12.7,-17.79) 23(12.7,-15.25) 24(12.7,-12.71) 25(12.7,-10.17) 26(12.7,-7.63) 27(12.7,-5.09) 28(12.7,-2.55) 29(12.7,-0.01) 30(12.7,2.53) 31(12.7,5.07) 32(12.7,7.61) 33(12.7,10.15) 34(12.7,12.69) 35(12.7,15.23) 36(12.7,17.77) 37(12.7,20.31) 38(12.7,22.85)
Top Overlay:
  circle w0.2: c-14.57,22.97 r0.1
  lines w0.5: -14.224,-24.257 -14.224,24.384 -9,24.384 -9,30.3 9,30.3 9,24.384 14.097,24.384 14.097,-24.257 4.06,-24.257 4.06,-25 -4.07,-25 -4.07,-24.257 -14.224,-24.257
  text "ESP-32 WROOM / DEVKIT" at -6.477,22.225 h3.05
  text "USB" at -2.286,-24.003 h1.52
Mechanical 13:
  circle w0.2: c-14.57,22.97 r0.1

## UC_ESP32S3WROOM [mm] "LB-2025-01-10"
pads (49):
  rrect20% 1.5x0.9 smd paste-0.02 mask+0.05: 1(-8.75,5.26) 1(8.75,5.26) 2(-8.75,3.99) 3(-8.75,2.72) 4(-8.75,1.45) 5(-8.75,0.18) 6(-8.75,-1.09) 7(-8.75,-2.36) 8(-8.75,-3.63) 9(-8.75,-4.9) 10(-8.75,-6.17) 11(-8.75,-7.44) 12(-8.75,-8.71) 13(-8.75,-9.98) 14(-8.75,-11.25) 27(8.75,-11.25) 28(8.75,-9.98) 29(8.75,-8.71) 30(8.75,-7.44) 31(8.75,-6.17) 32(8.75,-4.9) 33(8.75,-3.63) 34(8.75,-2.36) 35(8.75,-1.09) 36(8.75,0.18) 37(8.75,1.45) 38(8.75,2.72) 39(8.75,3.99)
  rrect20% 0.9x0.9 smd paste-0.02 mask+0.05: 1(-2.9,-3.86) 1(-2.9,-2.46) 1(-2.9,-1.06) 1(-1.5,-3.86) 1(-1.5,-2.46) 1(-1.5,-1.06) 1(-0.1,-3.86) 1(-0.1,-2.46) 1(-0.1,-1.06)
  rrect20% 0.9x1.5 smd paste-0.02 mask+0.05: 15(-6.985,-12.5) 16(-5.715,-12.5) 17(-4.445,-12.5) 18(-3.175,-12.5) 19(-1.905,-12.5) 20(-0.635,-12.5) 21(0.635,-12.5) 22(1.905,-12.5) 23(3.175,-12.5) 24(4.445,-12.5) 25(5.715,-12.5) 26(6.985,-12.5)
Top Overlay:
  lines w0.1: -10.1,5.4 ccw(c-10.05,5.4) -10,5.4 ccw(c-10.05,5.4) -10.1,5.4
  lines w0.2: -9,7 -9,12.75 9,12.75 9,7

## UC_Pro Micro 32U4 [mm] "LB-2024-04-18"
pads (24):
  round 1.85 hole 0.85 mask+0.05: J3_1(-7.62,-15.24) J3_2(-7.62,-12.7) J3_3(-7.62,-10.16) J3_4(-7.62,-7.62) J3_5(-7.62,-5.08) J3_6(-7.62,-2.54) J3_7(-7.62,0) J3_8(-7.62,2.54) J3_9(-7.62,5.08) J3_10(-7.62,7.62) J3_11(-7.62,10.16) J3_12(-7.62,12.7) J4_1(7.62,12.7) J4_2(7.62,10.16) J4_3(7.62,7.62) J4_4(7.62,5.08) J4_5(7.62,2.54) J4_6(7.62,0) J4_7(7.62,-2.54) J4_8(7.62,-5.08) J4_9(7.62,-7.62) J4_10(7.62,-10.16) J4_11(7.62,-12.7) J4_12(7.62,-15.24)
Top Overlay:
  lines w0.127: -4.32,16.51 -4.32,17.855 4.32,17.855 4.32,16.51 ; -8.89,-16.51 -8.89,16.51 8.89,16.51 8.89,-16.51 -8.89,-16.51
Mechanical 13:
  lines w0.127: -8.89,-16.51 -8.89,16.51 -4.32,16.51 4.32,16.51 8.89,16.51 8.89,-16.51 -8.89,-16.51

## UC_SMD_ESP32 Chip [mm] "LB-2024-04-18"
pads (47):
  rrect15% 2x0.9 smd paste-0.02 mask+0.05: 1(-8.5,5.26) 2(-8.5,3.99) 3(-8.5,2.72) 4(-8.5,1.45) 5(-8.5,0.18) 6(-8.5,-1.09) 7(-8.5,-2.36) 8(-8.5,-3.63) 9(-8.5,-4.9) 10(-8.5,-6.17) 11(-8.5,-7.44) 12(-8.5,-8.71) 13(-8.5,-9.98) 14(-8.5,-11.25) 25(8.5,-11.25) 26(8.5,-9.98) 27(8.5,-8.71) 28(8.5,-7.44) 29(8.5,-6.17) 30(8.5,-4.9) 31(8.5,-3.63) 32(8.5,-2.36) 33(8.5,-1.09) 34(8.5,0.18) 35(8.5,1.45) 36(8.5,2.72) 37(8.5,3.99) 38(8.5,5.26)
  rrect15% 0.9x2 smd paste-0.02 mask+0.05: 15(-5.715,-12.25) 16(-4.445,-12.25) 17(-3.175,-12.25) 18(-1.905,-12.25) 19(-0.635,-12.25) 20(0.635,-12.25) 21(1.905,-12.25) 22(3.175,-12.25) 23(4.445,-12.25) 24(5.715,-12.25)
  rrect15% 1.33x1.33 smd paste-0.02 mask+0.05: 39(-2.835,-4.075) 39(-2.835,-2.24) 39(-2.835,-0.405) 39(-1,-4.075) 39(-1,-2.24) 39(-1,-0.405) 39(0.835,-4.075) 39(0.835,-2.24) 39(0.835,-0.405)
Top Overlay:
  circle w0.25: c-10.275,5.185 r0.125
  lines w0.2: -9.05,-12.075 -9.05,-12.8 -6.54,-12.8 ; -9.05,6.085 -9.05,12.8 ; 6.54,-12.8 9.05,-12.8 9.05,-12.075 ; 9.05,6.085 9.05,12.8 ; -9.05,12.8 9.05,12.8 ; -9.05,12.8 9.05,12.8
Keep-Out Layer:
  rectangle: -9,6.45 9,12.75
  rectangle: -9,6.45 9,12.75
Mechanical 5:
Mechanical 16:
  lines w0.1: -0.5,0 0.5,0 ; 0,-0.5 0,0.5

## UC_WemosLolin32 [mm] "LB-2024-04-20"
pads (36):
  round 1.85 hole 0.85: 1(-11.43,24.13) 1(11.43,-6.35) 1(11.43,16.51) 2(-11.43,21.59) 3(-11.43,19.05) 4(-11.43,16.51) 5(-11.43,13.97) 6(-11.43,11.43) 7(-11.43,8.89) 8(-11.43,6.35) 9(-11.43,3.81) 10(-11.43,1.27) 11(-11.43,-1.27) 12(-11.43,-3.81) 13(-11.43,-6.35) 14(-11.43,-8.89) 15(-11.43,-11.43) 16(-11.43,-13.97) 16(11.43,-19.05) 16(11.43,6.35) 16(11.43,8.89) 16(11.43,24.13) 17(11.43,21.59) 18(11.43,19.05) 19(11.43,13.97) 20(11.43,11.43) 21(11.43,3.81) 22(11.43,1.27) 23(11.43,-1.27) 24(11.43,-3.81) 25(11.43,-8.89) 26(11.43,-11.43) 27(11.43,-13.97) 28(11.43,-16.51) 29(11.43,-21.59) 30(11.43,-24.13)
Top Overlay:
  lines w0.254: -7.18,-23.67 -4.68,-23.67 ; -7.18,-19.67 -4.68,-19.67 ; -0.68,-24.17 -0.68,-27.17 -1.18,-27.17 ; 0.07,31.83 9,31.83 9,7 -9,7 -9,31.75 -9,25 9,25 ; 5.32,-27.17 5.32,-24.17 ; -1.18,-27.17 -1.18,-26.67 -1.18,-24.17 5.82,-24.17 5.82,-26.67 ; -1.18,-27.17 5.82,-27.17 5.82,-26.67 ; 5.82,-26.67 12.82,-26.67 ; 12.82,-26.67 -12.68,-26.67 -12.68,31.83 12.82,31.83 12.82,-26.67 ; -11.18,-24.67 -11.18,-18.67 -7.18,-18.67 -7.18,-24.67 -11.18,-24.67
  text "Design by / Braun Leo E." at 4,7.25 h0.5
  text "Espressif / ESP-WROOM-32" at -8.75,21.25 h1

## V_MODULE_DM-OLED096-636 [mm]
height 11.3
pads (8):
  rect 2x2 hole 1: 1(-3.81,11.5)
  round 2 hole 1: 2(-1.27,11.5) 3(1.27,11.5) 4(3.81,11.5)
  round 3 hole 2: S1(-11,11) S2(11,11) S3(11,-11) S4(-11,-11)
Top Overlay:
  circle w0.2: c-4,13.5 r0.1
  lines w0.127: -13,-13 -13,13 13,13 13,-13 7,-13 7,-11 -7,-11 -7,-13 -13,-13
Mechanical 13:
  circle w0.2: c-4,13.5 r0.1
  lines w0.127: -13,-13 -13,13 13,13 13,-13 7,-13 7,-11 -7,-11 -7,-13 -13,-13
Mechanical 15:
  lines w0.05: -13.25,-13.25 -13.25,13.25 13.25,13.25 13.25,-13.25 -13.25,-13.25
3D body "step_temp.STEP": height 5.66, standoff -5.64, extent -13,-13 13,13

## V_MODULE_LCD-16X2 [mm] "LB-2024-11-29"
height 14
pads (20):
  rect 1.95x1.95 hole 0.95: 1(-32,15.5)
  round 1.95 hole 0.95: 2(-29.46,15.5) 3(-26.92,15.5) 4(-24.38,15.5) 5(-21.84,15.5) 6(-19.3,15.5) 7(-16.76,15.5) 8(-14.22,15.5) 9(-11.68,15.5) 10(-9.14,15.5) 11(-6.6,15.5) 12(-4.06,15.5) 13(-1.52,15.5) 14(1.02,15.5) 15(3.56,15.5) 16(6.1,15.5)
  round 2.8 hole 2.8 unplated: ""(-37.5,-15.5) ""(-37.5,15.5) ""(37.5,-15.5) ""(37.5,15.5)
Top Overlay:
  circle w0.2: c-40.75,15.5 r0.1
  lines w0.127: -40,-18 -40,18 40,18 40,-18 -40,-18 ; -35.65,-13.15 -35.65,13.15 35.65,13.15 35.65,-13.15 -35.65,-13.15 ; -32.25,-8.2 -32.25,8.2 32.25,8.2 32.25,-8.2 -32.25,-8.2
Mechanical 13:
  circle w0.2: c-40.75,15.5 r0.1

## V_THT_7Segement-Kl. [mm] "LB-2024-04-19"
pads (18):
  rect 1.85x1.85 hole 0.85: 1(-10.16,-10.16)
  round 1.85 hole 0.85: 2(-7.62,-10.16) 3(-5.08,-10.16) 4(-2.54,-10.16) 5(0,-10.16) 6(2.54,-10.16) 7(5.08,-10.16) 8(7.62,-10.16) 9(10.16,-10.16) 10(10.16,5.08) 11(7.62,5.08) 12(5.08,5.08) 13(2.54,5.08) 14(0,5.08) 15(-2.54,5.08) 16(-5.08,5.08) 17(-7.62,5.08) 18(-10.16,5.08)
Top Overlay:
  circle w0.254: c11.811,-7.696 r0.508
  circle w0.254: c-4.064,-7.62 r0.508
  rectangle: 11.405,-8.103 12.217,-7.239
  rectangle: -4.47,-8.026 -3.607,-7.188
  lines w0.254: -13.97,-12.065 13.335,-12.065 13.335,6.985 -13.97,6.985 -13.97,-12.065
  lines w0.508: -11.176,-7.112 -11.176,-3.048 ; -11.176,-2.032 -11.176,2.032 ; -10.668,-7.62 -6.604,-7.62 ; -10.668,-2.54 -6.604,-2.54 ; -10.668,2.54 -6.604,2.54 ; -6.096,-7.112 -6.096,-3.048 ; -6.096,-2.032 -6.096,2.032 ; 5.08,-7.112 5.08,-3.048 ; 5.08,-2.032 5.08,2.032 ; 5.588,-7.62 9.652,-7.62 ; 5.588,-2.54 9.652,-2.54 ; 5.588,2.54 9.652,2.54 ; 10.16,-7.112 10.16,-3.048 ; 10.16,-2.032 10.16,2.032

## V_THT_7Segment-CP [mm] "LB-2024-04-19"
pads (10):
  rect 1.85x1.85 hole 0.85: 1(-5.08,-7.62)
  round 1.85 hole 0.85: 2(-2.54,-7.62) 3(0,-7.62) 4(2.54,-7.62) 5(5.08,-7.62) 6(5.08,7.62) 7(2.54,7.62) 8(0,7.62) 9(-2.54,7.62) 10(-5.08,7.62)
Top Overlay:
  circle w0.508: c10.414,-4.064 r0.254
  circle w0.508: c-2.286,-4.318 r0.254
  lines w0.254: 0,10.16 12.7,10.16 ; 12.7,10.16 12.7,-10.16 -12.7,-10.16 -12.7,10.16 12.7,10.16
  lines w0.381: -8.89,-4.572 -8.89,-0.254 ; -8.89,0.508 -8.89,4.826 ; -8.382,-4.826 -4.318,-4.826 ; -8.382,0.254 -4.318,0.254 ; -8.382,5.334 -4.318,5.334 ; -3.81,-4.572 -3.81,-0.254 ; -3.81,0.508 -3.81,4.826 ; 3.81,-4.318 3.81,0 ; 3.81,0.762 3.81,5.08 ; 4.318,-4.572 8.382,-4.572 ; 4.318,0.508 8.382,0.508 ; 4.318,5.588 8.382,5.588 ; 8.89,-4.318 8.89,0 ; 8.89,0.762 8.89,5.08

## V_THT_7Segment-Gr. [mm] "LB-2024-04-19"
pads (18):
  rect 1.85x1.85 hole 0.85: 1(-10.16,-10.16)
  round 1.85 hole 0.85: 2(-7.62,-10.16) 3(-5.08,-10.16) 4(-2.54,-10.16) 5(0,-10.16) 6(2.54,-10.16) 7(5.08,-10.16) 8(7.62,-10.16) 9(10.16,-10.16) 10(10.16,12.065) 11(7.62,12.065) 12(5.08,12.065) 13(2.54,12.065) 14(0,12.065) 15(-2.54,12.065) 16(-5.08,12.065) 17(-7.62,12.065) 18(-10.16,12.065)
Top Overlay:
  circle w0.254: c11.811,-4.521 r0.508
  circle w0.254: c-4.064,-4.445 r0.508
  rectangle: 11.405,-4.928 12.217,-4.064
  rectangle: -4.47,-4.851 -3.607,-4.013
  lines w0.254: -17.78,-12.7 17.78,-12.7 17.78,15.24 -17.78,15.24 -17.78,-12.7
  lines w0.508: -11.176,-3.937 -11.176,0.127 ; -11.176,1.143 -11.176,5.207 ; -10.668,-4.445 -6.604,-4.445 ; -10.668,0.635 -6.604,0.635 ; -10.668,5.715 -6.604,5.715 ; -6.096,-3.937 -6.096,0.127 ; -6.096,1.143 -6.096,5.207 ; 5.08,-3.937 5.08,0.127 ; 5.08,1.143 5.08,5.207 ; 5.588,-4.445 9.652,-4.445 ; 5.588,0.635 9.652,0.635 ; 5.588,5.715 9.652,5.715 ; 10.16,-3.937 10.16,0.127 ; 10.16,1.143 10.16,5.207

## V_THT_HCS12SS59T [mm] "LB-2026-01-02"
pads (15):
  rect 1.2x2.5 hole 0.75: 1(0,0) 2(-2,0) 44(-86,0) 45(-88,0)
  oval 1.2x2.5 hole 0.75: 5(-8,0) 6(-10,0) 7(-12,0) 8(-14,0) 9(-16,0) 10(-18,0) 11(-20,0) 12(-22,0) 39(-76,0) 40(-78,0) 41(-80,0)
Top Overlay:
  lines w0.4: -94,-23 6,-23 6,-2.5 -94,-2.5 -94,-23 ; -80.5,-17.5 -80.5,-8.5 -6.5,-8.5 -6.5,-17.5 -80.5,-17.5

## V_THT_ILI9341 [mm] "LB-2024-04-19"
pads (22):
  rect 2.15x2.15 hole 1.15: A1(-3.81,40.88) B1(-16.51,-40.88)
  round 2.15 hole 1.15: A2(-1.27,40.88) A3(1.27,40.88) A4(3.81,40.88) B2(-13.97,-40.88) B3(-11.43,-40.88) B4(-8.89,-40.88) B5(-6.35,-40.88) B6(-3.81,-40.88) B7(-1.27,-40.88) B8(1.27,-40.88) B9(3.81,-40.88) B10(6.35,-40.88) B11(8.89,-40.88) B12(11.43,-40.88) B13(13.97,-40.88) B14(16.51,-40.88)
  round 3.81 hole 2.54: MH(-22,-39.73) MH(-22,40.27) MH(22,-39.73) MH(22,40.27)
Top Overlay:
  lines w0.1: -3.81,46.92 cw(c-3.81,46.97) -3.81,47.02 cw(c-3.81,46.97) -3.81,46.92
  lines w0.5: -25,-31.73 25,-31.73 ; -25,38.27 25,38.27 ; -25,-42.73 -25,43.27 25,43.27 25,1.27 25,-42.73 -25,-42.73

## V_THT_WM-C1610M [mm] "LB-2024-04-19"
pads (16):
  round 1.85 hole 0.85: 1(-32,15.5) 2(-29.46,15.5) 3(-26.92,15.5) 4(-24.38,15.5) 5(-21.84,15.5) 6(-19.3,15.5) 7(-16.76,15.5) 8(-14.22,15.5) 9(-11.68,15.5) 10(-9.14,15.5) 11(-6.6,15.5) 12(-4.06,15.5) 13(-1.52,15.5) 14(1.02,15.5) 15(3.56,15.5) 16(6.1,15.5)
Top Overlay:
  circle w0.2: c-37.51,15.538 r1.25
  circle w0.2: c-37.51,-15.462 r1.25
  circle w0.2: c37.49,15.538 r1.25
  circle w0.2: c37.49,6.538 r0.5
  circle w0.2: c37.49,2.578 r0.5
  circle w0.2: c37.49,-2.502 r0.5
  circle w0.2: c37.49,-6.462 r0.5
  circle w0.2: c37.49,-15.462 r1.25
  lines w0.1: -38.75,-15.462 -36.26,-15.462 ; -38.75,15.538 -36.26,15.538 ; -37.51,-16.75 -37.51,-14.25 ; -37.51,14.25 -37.51,16.75 ; 36.25,-15.462 38.74,-15.462 ; 36.25,15.538 38.74,15.538 ; 37.49,-16.75 37.49,-14.25 ; 37.49,14.25 37.49,16.75
  lines w0.2: -33.01,15.498 -33.01,18.038 ; -31.01,15.498 -31.01,18.038 ; -30.47,15.498 -30.47,18.038 ; -28.47,15.498 -28.47,18.038 ; -27.93,15.338 -27.93,18.038 ; -25.93,15.338 -25.93,18.038 ; -25.39,15.498 -25.39,18.038 ; -23.39,15.498 -23.39,18.038 ; -22.85,15.498 -22.85,18.038 ; -20.85,15.498 -20.85,18.038 ; -20.31,15.498 -20.31,18.038 ; -18.31,15.498 -18.31,18.038 ; -17.77,15.498 -17.77,18.038 ; -15.77,15.498 -15.77,18.038 ; -15.23,15.498 -15.23,18.038 ; -13.23,15.498 -13.23,18.038 ; -12.69,15.498 -12.69,18.038 ; -10.69,15.498 -10.69,18.038 ; -10.15,15.468 -10.15,18.038 ; -8.15,15.468 -8.15,18.038 ; -7.61,15.468 -7.61,18.038 ; -5.61,15.468 -5.61,18.038 ; -5.07,15.498 -5.07,18.038 ; -3.07,15.498 -3.07,18.038 ; -2.53,15.498 -2.53,18.038 ; -0.53,15.498 -0.53,18.038 ; 0.01,15.498 0.01,18.038 ; 2.01,15.498 2.01,18.038 ; 2.55,15.498 2.55,18.038 ; 4.55,15.498 4.55,18.038 ; 5.09,15.498 5.09,18.038 ; 7.09,15.498 7.09,18.038 ; 35.59,-7.962 39.99,-7.962 ; 35.59,-4.962 39.99,-4.962 ; 35.59,-4.002 39.99,-4.002 ; 35.59,-1.002 39.99,-1.002 ; 35.59,1.078 39.99,1.078 ; 35.59,4.078 39.99,4.078 ; 35.59,5.038 39.99,5.038 ; 35.59,8.038 39.99,8.038 ; -40.01,-17.962 39.99,-17.962 39.99,18.038 -40.01,18.038 -40.01,-17.962 ; -35.61,-12.562 -35.61,12.638 35.59,12.638 35.59,-12.562 -35.61,-12.562 ; -32.24,-7.462 32.22,-7.462 32.22,7.538 -32.24,7.538 -32.24,-7.462

## VSON-10 [mm] "LB-2024-09-01"
pads (15):
  rrect15% 0.6x0.24 smd paste-0.02 mask+0.05: 1(-1.4,1) 2(-1.4,0.5) 3(-1.4,0) 4(-1.4,-0.5) 5(-1.4,-1) 6(1.4,-1) 7(1.4,-0.5) 8(1.4,0) 9(1.4,0.5) 10(1.4,1)
  rect 1.65x2.4 smd paste-0.02 mask+0.05: 11(0,0)
  round 0.3 hole 0.2 mask+0: 12(0,-0.95) 13(-0.575,0) 14(0.575,0) 15(0,0.95)
Top Layer:
  region: 0.375,1.2 0.825,1.2 0.825,-1.2 0.375,-1.2 0.375,-1.7 0.125,-1.7 0.125,-1.2 -0.125,-1.2 -0.125,-1.7 -0.375,-1.7 -0.375,-1.2 -0.825,-1.2 -0.825,1.2 -0.375,1.2 -0.375,1.7 -0.125,1.7 -0.125,1.2 0.125,1.2 0.125,1.7 0.375,1.7
Top Overlay:
  circle w0.2: c-2.395,1.2 r0.1
  lines w0.127: -1.5,-1.5 -0.695,-1.5 ; -1.5,1.5 -0.695,1.5 ; 0.695,-1.5 1.5,-1.5 ; 0.695,1.5 1.5,1.5
Top Paste:
  region: -0.125,1.36 -0.375,1.36 -0.375,1.7 -0.125,1.7
  region: 0.375,1.36 0.125,1.36 0.125,1.7 0.375,1.7
  region: 0.375,-1.7 0.125,-1.7 0.125,-1.36 0.375,-1.36
  region: -0.125,-1.7 -0.375,-1.7 -0.375,-1.36 -0.125,-1.36
  region: 0.75,0.1 -0.75,0.1 -0.75,1.16 0.75,1.16
  region: 0.75,-1.16 -0.75,-1.16 -0.75,-0.1 0.75,-0.1
Mechanical 13:
  circle w0.2: c-2.395,1.2 r0.1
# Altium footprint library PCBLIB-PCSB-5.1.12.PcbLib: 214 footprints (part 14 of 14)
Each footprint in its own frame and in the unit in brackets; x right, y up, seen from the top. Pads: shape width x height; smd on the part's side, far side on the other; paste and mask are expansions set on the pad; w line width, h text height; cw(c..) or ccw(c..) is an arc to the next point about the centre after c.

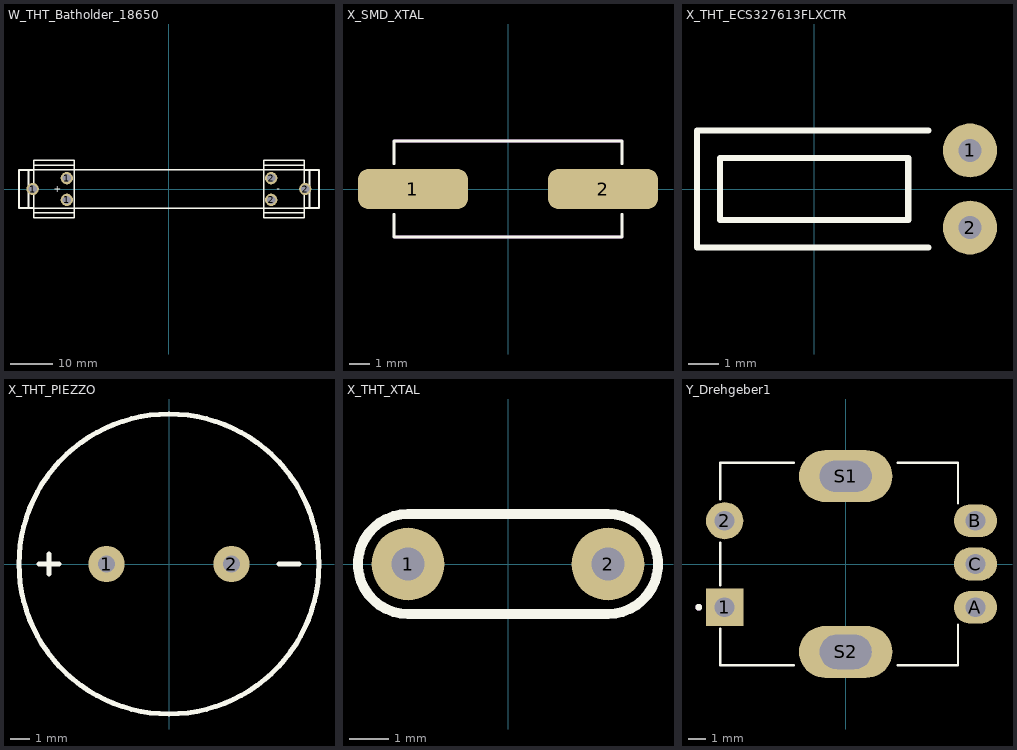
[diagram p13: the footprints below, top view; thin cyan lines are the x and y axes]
## W_THT_Batholder_18650 [mm] "LB-2024-04-25"
height 17
pads (6):
  round 2.9 hole 1.9: 1(-32,0) 1(-24,-2.54) 1(-24,2.54) 2(24.006,-2.54) 2(24.006,2.54) 2(32,0)
Top Overlay:
  lines w0.4: -31.74,-6.75 -22.27,-6.75 ; -31.74,-6.71 -31.74,-5.552 -29.08,-5.552 -22.272,-5.552 ; -31.74,-5.492 -31.74,5.552 ; -31.74,-4.45 -35.22,-4.45 -35.22,4.45 -31.74,4.45 ; -31.74,6.71 -31.74,5.552 ; -31.74,6.75 -22.27,6.75 ; -22.272,5.552 -29.08,5.552 -31.74,5.552 ; -22.22,-6.75 -22.22,-5.552 -22.22,5.552 -22.22,6.75 ; 22.226,-6.75 22.226,-5.552 22.226,5.552 22.226,6.75 ; 22.276,-6.75 31.746,-6.75 ; 22.276,6.75 31.746,6.75 ; 22.278,-5.552 29.086,-5.552 31.746,-5.552 ; 22.278,5.552 29.086,5.552 31.746,5.552 31.746,6.71 ; 31.746,-6.71 31.746,-5.552 ; 31.746,-4.45 35.226,-4.45 35.226,4.45 31.746,4.45 ; 31.746,5.492 31.746,-5.552 ; -33,-4.5 33,-4.5 33,0 33,4.5 -33,4.5 -33,0 -33,-4.5
  text "+" at -25.3,0.7 h1.52
  text "-" at 25.3,-0.7 h1.52

## X_SMD_XTAL [mm] "LB-2024-04-17"
pads (2):
  rrect50% 5.5x2 smd paste-0.02 mask+0.05: 1(-4.75,0) 2(4.75,0)
Top Overlay:
  lines w0.127: -5.7,-1.254 -5.7,-2.4 5.7,-2.4 5.7,-1.254 ; -5.7,1.254 -5.7,2.4 5.7,2.4 5.7,1.254
Mechanical 13:
  lines w0.127: -5.7,-2.4 5.7,-2.4 ; -5.7,2.4 5.7,2.4

## X_THT_ECS327613FLXCTR [mm] "LB-2025-06-22"
pads (2):
  round 1.75 hole 0.75: 1(5.05,1.25) 2(5.05,-1.25)
Top Overlay:
  lines w0.2: 3.7,-1.9 -3.8,-1.9 -3.8,1.9 3.7,1.9 ; 3.05,-1 3.05,1 ; 3.05,-1 3.05,1 ; 3.05,-1 2.8,-1 3.05,-1 ; 3.05,-1 -3.05,-1 -3.05,1 3.05,1 ; 3.05,1 2.8,1 3.05,1
Mechanical 13:
  lines w0.1: 3.05,-1 3.05,1

## X_THT_PIEZZO [mm] "LB-2024-04-18"
pads (2):
  round 1.85 hole 0.85: 1(-3.175,0) 2(3.175,0)
Top Overlay:
  circle w0.254: c0,0 r7.62
  lines w0.254: -6.604,0 -5.588,0 ; -6.096,-0.508 -6.096,0.508 ; 5.588,0 6.604,0

## X_THT_XTAL [mm] "LB-2024-04-17"
pads (2):
  round 1.85 hole 0.85: 1(-2.54,0) 2(2.54,0)
Top Overlay:
  lines w0.254: -2.54,-1.27 cw(c-2.54,0) -2.54,1.27 2.54,1.27 cw(c2.54,0) 2.54,-1.27 -2.54,-1.27

## Y_Drehgeber1 [mm] "LB-2024-04-19"
pads (7):
  rect 2.15x2.15 hole 1.15: 1(-7,-2.5)
  round 2.15 hole 1.15: 2(-7,2.5)
  oval 2.5x1.9 hole 1.15: A(7.5,-2.5) B(7.5,2.5) C(7.5,0)
  oval 5.4x3 hole 1.8 slot 3 at 0 deg: S1(0,5.08)
  oval 5.4x3 hole 2 slot 3 at 0 deg: S2(0,-5.08)
Top Overlay:
  circle w0.2: c-8.5,-2.5 r0.1
  lines w0.127: -7.25,-3.75 -7.25,-5.85 -3,-5.85 ; -7.25,-1.25 -7.25,1.25 ; -7.25,3.75 -7.25,5.85 -3,5.85 ; 3,-5.85 6.5,-5.85 6.5,-3.5 ; 3,5.85 6.5,5.85 6.5,3.5
Mechanical 13:
  circle w0.2: c-8.5,-2.5 r0.1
